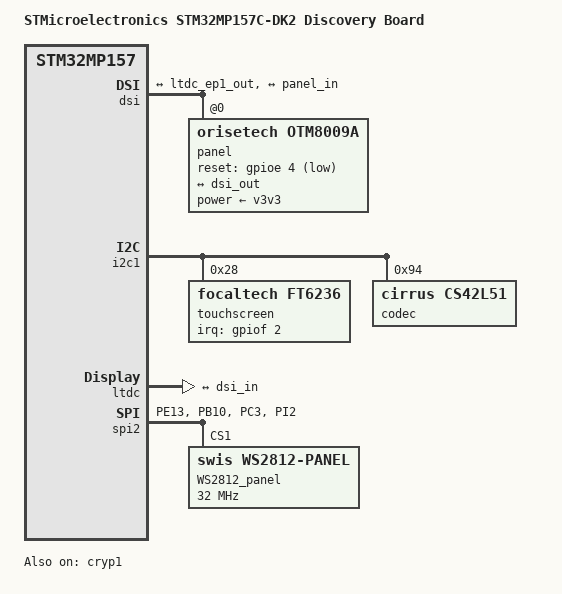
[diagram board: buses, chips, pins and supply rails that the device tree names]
// SPDX-License-Identifier: (GPL-2.0+ OR BSD-3-Clause)
/*
 * Copyright (C) STMicroelectronics 2019 - All Rights Reserved
 * Author: Alexandre Torgue <alexandre.torgue@st.com> for STMicroelectronics.
 */

/dts-v1/;

#include "stm32mp157.dtsi"
#include "stm32mp15xc.dtsi"
#include "stm32mp15-pinctrl.dtsi"
#include "stm32mp15xxac-pinctrl.dtsi"
#include "stm32mp15xx-dkx.dtsi"

/ {
	model = "STMicroelectronics STM32MP157C-DK2 Discovery Board";
	compatible = "st,stm32mp157c-dk2", "st,stm32mp157";

	aliases {
		ethernet0 = &ethernet0;
		serial0 = &uart4;
		serial1 = &usart3;
		serial2 = &uart7;
		serial3 = &usart2;
	};

	chosen {
		stdout-path = "serial0:115200n8";
	};
};

&cryp1 {
	status = "okay";
};

&dsi {
	status = "okay";
	phy-dsi-supply = <&reg18>;

	ports {
		port@0 {
			reg = <0>;
			dsi_in: endpoint {
				remote-endpoint = <&ltdc_ep1_out>;
			};
		};

		port@1 {
			reg = <1>;
			dsi_out: endpoint {
				remote-endpoint = <&panel_in>;
			};
		};
	};

	panel@0 {
		compatible = "orisetech,otm8009a";
		reg = <0>;
		reset-gpios = <&gpioe 4 GPIO_ACTIVE_LOW>;
		power-supply = <&v3v3>;
		status = "okay";

		port {
			panel_in: endpoint {
				remote-endpoint = <&dsi_out>;
			};
		};
	};
};

&i2c1 {
	touchscreen@28 {
		compatible = "focaltech,ft6236";
		reg = <0x28>;
		interrupts = <2 2>;
		interrupt-parent = <&gpiof>;
		interrupt-controller;
		touchscreen-size-x = <480>;
		touchscreen-size-y = <800>;
		status = "okay";
	};

	codec@94 {
		compatible = "cirrus,cs42l51";
		reg = <0x94>;
		status = "okay";
	};
};

&ltdc {
	status = "okay";

	port {
		ltdc_ep1_out: endpoint@1 {
			reg = <1>;
			remote-endpoint = <&dsi_in>;
		};
	};
};

&usart2 {
	pinctrl-names = "default", "sleep", "idle";
	pinctrl-0 = <&usart2_pins_c>;
	pinctrl-1 = <&usart2_sleep_pins_c>;
	pinctrl-2 = <&usart2_idle_pins_c>;
	status = "disabled";
};

&spi2 {
    pinctrl-names = "default";
    pinctrl-0 = <&spi2_pins_b>;
	status = "okay";
	cs-gpio = <&gpiog 3 0>, <&gpioe 1 0>, <&gpiof 3 0>;
	#address-cells = <1>;
	#size-cells = <0>;

    WS2812_panel: WS2812_panel@1{
        compatible = "swis,ws2812-panel";
        reg = <1>;
        spi-max-frequency = <32000000>;
		panel,x-visible-len = <8>;
		panel,y-visible-len = <8>;
		panel,color-bits = <8>;
		panel,green-bit-offset = <0>;
		panel,red-bit-offset = <8>;
		panel,blue-bit-offset = <16>;
		status = "okay";
    };
};
/* One should create spi4_pins_b in stm32mp15-pinctrl.dtsi
because spi4_pins_a doesnt align with hardware

	spi4_pins_b: spi4-0 {
		pins {
			pinmux = <STM32_PINMUX('E', 12, AF5)>, /* SPI4_SCK */
				 <STM32_PINMUX('E', 14, AF5)>;  /* SPI4_MOSI ARD_D11 Connector*/
			bias-pull-down;
			drive-push-pull;
			slew-rate = <1>;
		};
		pins2 {
			pinmux = <STM32_PINMUX('E', 13, AF5)>; /* SPI4_MISO */
			bias-disable;
		};
	};

	spi2_pins_b: spi2-0 {
		pins1 {
			pinmux = <STM32_PINMUX('B', 10, AF5)>, /* SPI1_SCK */
				 <STM32_PINMUX('C', 3, AF5)>; /* SPI2_MOSI ADC1_IN13 connector on CN17*/
			bias-disable;
			drive-push-pull;
			slew-rate = <1>;
		};

		pins2 {
			pinmux = <STM32_PINMUX('I', 2, AF5)>; /* SPI1_MISO */
			bias-disable;
		};
	};

setting reg = <0> in device causes error with conflicting
chip select usage (spi: chipselect 0 already in use),
setting reg = <1> fixes that

*/

